VERSION 5.7 ;
  NOWIREEXTENSIONATPIN ON ;
  DIVIDERCHAR "/" ;
  BUSBITCHARS "[]" ;
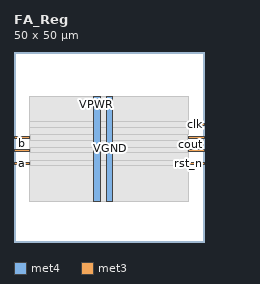
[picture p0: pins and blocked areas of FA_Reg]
MACRO FA_Reg
  CLASS BLOCK ;
  FOREIGN FA_Reg ;
  ORIGIN 0.000 0.000 ;
  SIZE 50.000 BY 50.000 ;
  PIN VGND
    DIRECTION INOUT ;
    USE GROUND ;
    PORT
      LAYER met4 ;
        RECT 24.340 10.640 25.940 38.320 ;
    END
  END VGND
  PIN VPWR
    DIRECTION INOUT ;
    USE POWER ;
    PORT
      LAYER met4 ;
        RECT 21.040 10.640 22.640 38.320 ;
    END
  END VPWR
  PIN a
    DIRECTION INPUT ;
    USE SIGNAL ;
    ANTENNAGATEAREA 0.196500 ;
    PORT
      LAYER met3 ;
        RECT 0.000 20.440 4.000 21.040 ;
    END
  END a
  PIN b
    DIRECTION INPUT ;
    USE SIGNAL ;
    ANTENNAGATEAREA 0.196500 ;
    PORT
      LAYER met3 ;
        RECT 0.000 23.840 4.000 24.440 ;
    END
  END b
  PIN cin
    DIRECTION INPUT ;
    USE SIGNAL ;
    ANTENNAGATEAREA 0.196500 ;
    PORT
      LAYER met3 ;
        RECT 0.000 27.240 4.000 27.840 ;
    END
  END cin
  PIN clk
    DIRECTION INPUT ;
    USE SIGNAL ;
    ANTENNAGATEAREA 0.852000 ;
    PORT
      LAYER met3 ;
        RECT 46.000 30.640 50.000 31.240 ;
    END
  END clk
  PIN cout
    DIRECTION OUTPUT ;
    USE SIGNAL ;
    ANTENNADIFFAREA 0.445500 ;
    PORT
      LAYER met3 ;
        RECT 46.000 27.240 50.000 27.840 ;
    END
  END cout
  PIN rst_n
    DIRECTION INPUT ;
    USE SIGNAL ;
    ANTENNAGATEAREA 0.196500 ;
    PORT
      LAYER met3 ;
        RECT 46.000 20.440 50.000 21.040 ;
    END
  END rst_n
  PIN sum
    DIRECTION OUTPUT ;
    USE SIGNAL ;
    ANTENNADIFFAREA 0.445500 ;
    PORT
      LAYER met3 ;
        RECT 46.000 23.840 50.000 24.440 ;
    END
  END sum
  OBS
      LAYER nwell ;
        RECT 5.330 10.795 44.350 38.165 ;
      LAYER li1 ;
        RECT 5.520 10.795 44.160 38.165 ;
      LAYER met1 ;
        RECT 4.210 10.640 44.160 38.320 ;
      LAYER met2 ;
        RECT 4.230 10.695 43.610 38.265 ;
      LAYER met3 ;
        RECT 3.990 31.640 46.000 38.245 ;
        RECT 3.990 30.240 45.600 31.640 ;
        RECT 3.990 28.240 46.000 30.240 ;
        RECT 4.400 26.840 45.600 28.240 ;
        RECT 3.990 24.840 46.000 26.840 ;
        RECT 4.400 23.440 45.600 24.840 ;
        RECT 3.990 21.440 46.000 23.440 ;
        RECT 4.400 20.040 45.600 21.440 ;
        RECT 3.990 10.715 46.000 20.040 ;
  END
END FA_Reg
END LIBRARY

